VERSION 5.8 ;
BUSBITCHARS "[]" ;
DIVIDERCHAR "/" ;

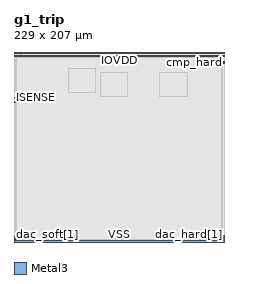
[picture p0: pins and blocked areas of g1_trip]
MACRO g1_trip
  CLASS BLOCK ;
  ORIGIN 0 0 ;
  FOREIGN g1_trip 0 0 ;
  SIZE 229 BY 207 ;
  SYMMETRY X Y ;
  PIN VREF
    DIRECTION INPUT ;
    USE SIGNAL ;
    PORT
      LAYER Metal3 ;
        RECT 0 152.35 1.5 152.65 ;
    END
  END VREF
  PIN ISENSE
    DIRECTION INPUT ;
    USE SIGNAL ;
    PORT
      LAYER Metal3 ;
        RECT 0 157.57 1.5 157.87 ;
    END
  END ISENSE
  PIN cmp_soft
    DIRECTION OUTPUT ;
    USE SIGNAL ;
    PORT
      LAYER Metal3 ;
        RECT 227.5 194.35 229 194.65 ;
    END
  END cmp_soft
  PIN cmp_hard
    DIRECTION OUTPUT ;
    USE SIGNAL ;
    PORT
      LAYER Metal3 ;
        RECT 227.5 195.55 229 195.85 ;
    END
  END cmp_hard
  PIN clk
    DIRECTION INPUT ;
    USE SIGNAL ;
    PORT
      LAYER Metal3 ;
        RECT 227.5 196.75 229 197.05 ;
    END
  END clk
  PIN VDD
    DIRECTION INOUT ;
    USE POWER ;
    PORT
      LAYER Metal3 ;
        RECT 0 205 229 207 ;
    END
  END VDD
  PIN IOVDD
    DIRECTION INOUT ;
    USE POWER ;
    PORT
      LAYER Metal3 ;
        RECT 0 202 229 203.5 ;
    END
  END IOVDD
  PIN VSS
    DIRECTION INOUT ;
    USE GROUND ;
    PORT
      LAYER Metal3 ;
        RECT 0 0 229 2 ;
    END
  END VSS
  PIN dac_soft[0]
    DIRECTION INPUT ;
    USE SIGNAL ;
    PORT
      LAYER Metal3 ;
        RECT 0 2.65 1.5 2.95 ;
    END
  END dac_soft[0]
  PIN dac_soft[1]
    DIRECTION INPUT ;
    USE SIGNAL ;
    PORT
      LAYER Metal3 ;
        RECT 0 3.25 1.5 3.55 ;
    END
  END dac_soft[1]
  PIN dac_soft[2]
    DIRECTION INPUT ;
    USE SIGNAL ;
    PORT
      LAYER Metal3 ;
        RECT 0 3.85 1.5 4.15 ;
    END
  END dac_soft[2]
  PIN dac_soft[3]
    DIRECTION INPUT ;
    USE SIGNAL ;
    PORT
      LAYER Metal3 ;
        RECT 0 4.45 1.5 4.75 ;
    END
  END dac_soft[3]
  PIN dac_soft[4]
    DIRECTION INPUT ;
    USE SIGNAL ;
    PORT
      LAYER Metal3 ;
        RECT 0 5.05 1.5 5.35 ;
    END
  END dac_soft[4]
  PIN dac_soft[5]
    DIRECTION INPUT ;
    USE SIGNAL ;
    PORT
      LAYER Metal3 ;
        RECT 0 5.65 1.5 5.95 ;
    END
  END dac_soft[5]
  PIN dac_soft[6]
    DIRECTION INPUT ;
    USE SIGNAL ;
    PORT
      LAYER Metal3 ;
        RECT 0 6.25 1.5 6.55 ;
    END
  END dac_soft[6]
  PIN dac_soft[7]
    DIRECTION INPUT ;
    USE SIGNAL ;
    PORT
      LAYER Metal3 ;
        RECT 0 6.85 1.5 7.15 ;
    END
  END dac_soft[7]
  PIN dac_hard[0]
    DIRECTION INPUT ;
    USE SIGNAL ;
    PORT
      LAYER Metal3 ;
        RECT 227.5 2.65 229 2.95 ;
    END
  END dac_hard[0]
  PIN dac_hard[1]
    DIRECTION INPUT ;
    USE SIGNAL ;
    PORT
      LAYER Metal3 ;
        RECT 227.5 3.25 229 3.55 ;
    END
  END dac_hard[1]
  PIN dac_hard[2]
    DIRECTION INPUT ;
    USE SIGNAL ;
    PORT
      LAYER Metal3 ;
        RECT 227.5 3.85 229 4.15 ;
    END
  END dac_hard[2]
  PIN dac_hard[3]
    DIRECTION INPUT ;
    USE SIGNAL ;
    PORT
      LAYER Metal3 ;
        RECT 227.5 4.45 229 4.75 ;
    END
  END dac_hard[3]
  PIN dac_hard[4]
    DIRECTION INPUT ;
    USE SIGNAL ;
    PORT
      LAYER Metal3 ;
        RECT 227.5 5.05 229 5.35 ;
    END
  END dac_hard[4]
  PIN dac_hard[5]
    DIRECTION INPUT ;
    USE SIGNAL ;
    PORT
      LAYER Metal3 ;
        RECT 227.5 5.65 229 5.95 ;
    END
  END dac_hard[5]
  PIN dac_hard[6]
    DIRECTION INPUT ;
    USE SIGNAL ;
    PORT
      LAYER Metal3 ;
        RECT 227.5 6.25 229 6.55 ;
    END
  END dac_hard[6]
  PIN dac_hard[7]
    DIRECTION INPUT ;
    USE SIGNAL ;
    PORT
      LAYER Metal3 ;
        RECT 227.5 6.85 229 7.15 ;
    END
  END dac_hard[7]
  OBS
    LAYER Metal1 ;
      RECT 0 0 229 207 ;
    LAYER Metal2 ;
      RECT 0 0 229 207 ;
    LAYER Metal3 ;
      RECT 1.8 2.5 227.2 201.7 ;
    LAYER Metal4 ;
      RECT 3 3 226 201.5 ;
      RECT 7 201.5 8 204.5 ;
      RECT 69 201.5 70 203.25 ;
      RECT 122 201.5 123 204.5 ;
      RECT 184 201.5 185 203.25 ;
    LAYER Metal5 ;
      RECT 3 3 226 201.5 ;
    LAYER TopMetal1 ;
      RECT 58.96 162.9 88.76 189.1 ;
      RECT 93.8 158.4 123.6 184.6 ;
      RECT 158.8 158.4 188.6 184.6 ;
  END
END g1_trip

END LIBRARY
